VERSION 5.7 ;
BUSBITCHARS "[]" ;
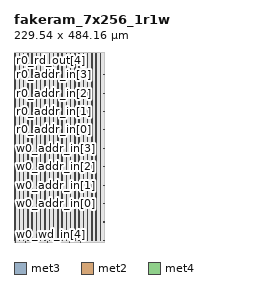
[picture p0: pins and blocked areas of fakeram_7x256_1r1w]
MACRO fakeram_7x256_1r1w
  FOREIGN fakeram_7x256_1r1w 0 0 ;
  SYMMETRY X Y R90 ;
  SIZE 229.540 BY 484.160 ;
  CLASS BLOCK ;
  PIN w0_wd_in[0]
    DIRECTION INPUT ;
    USE SIGNAL ;
    SHAPE ABUTMENT ;
    PORT
      LAYER met3 ;
      RECT 0.000 3.930 0.900 4.230 ;
    END
  END w0_wd_in[0]
  PIN w0_wd_in[1]
    DIRECTION INPUT ;
    USE SIGNAL ;
    SHAPE ABUTMENT ;
    PORT
      LAYER met3 ;
      RECT 0.000 50.850 0.900 51.150 ;
    END
  END w0_wd_in[1]
  PIN w0_wd_in[2]
    DIRECTION INPUT ;
    USE SIGNAL ;
    SHAPE ABUTMENT ;
    PORT
      LAYER met3 ;
      RECT 228.640 3.930 229.540 4.230 ;
    END
  END w0_wd_in[2]
  PIN w0_wd_in[3]
    DIRECTION INPUT ;
    USE SIGNAL ;
    SHAPE ABUTMENT ;
    PORT
      LAYER met3 ;
      RECT 228.640 50.850 229.540 51.150 ;
    END
  END w0_wd_in[3]
  PIN w0_wd_in[4]
    DIRECTION OUTPUT ;
    USE SIGNAL ;
    SHAPE ABUTMENT ;
    PORT
      LAYER met2 ;
      RECT 2.690 0.000 2.830 0.420 ;
    END
  END w0_wd_in[4]
  PIN w0_wd_in[5]
    DIRECTION OUTPUT ;
    USE SIGNAL ;
    SHAPE ABUTMENT ;
    PORT
      LAYER met2 ;
      RECT 30.290 0.000 30.430 0.420 ;
    END
  END w0_wd_in[5]
  PIN w0_wd_in[6]
    DIRECTION OUTPUT ;
    USE SIGNAL ;
    SHAPE ABUTMENT ;
    PORT
      LAYER met2 ;
      RECT 57.890 0.000 58.030 0.420 ;
    END
  END w0_wd_in[6]
  PIN r0_rd_out[0]
    DIRECTION OUTPUT ;
    USE SIGNAL ;
    SHAPE ABUTMENT ;
    PORT
      LAYER met2 ;
      RECT 85.490 0.000 85.630 0.420 ;
    END
  END r0_rd_out[0]
  PIN r0_rd_out[1]
    DIRECTION OUTPUT ;
    USE SIGNAL ;
    SHAPE ABUTMENT ;
    PORT
      LAYER met2 ;
      RECT 113.090 0.000 113.230 0.420 ;
    END
  END r0_rd_out[1]
  PIN r0_rd_out[2]
    DIRECTION OUTPUT ;
    USE SIGNAL ;
    SHAPE ABUTMENT ;
    PORT
      LAYER met2 ;
      RECT 140.690 0.000 140.830 0.420 ;
    END
  END r0_rd_out[2]
  PIN r0_rd_out[3]
    DIRECTION OUTPUT ;
    USE SIGNAL ;
    SHAPE ABUTMENT ;
    PORT
      LAYER met2 ;
      RECT 168.290 0.000 168.430 0.420 ;
    END
  END r0_rd_out[3]
  PIN r0_rd_out[4]
    DIRECTION OUTPUT ;
    USE SIGNAL ;
    SHAPE ABUTMENT ;
    PORT
      LAYER met2 ;
      RECT 2.690 483.740 2.830 484.160 ;
    END
  END r0_rd_out[4]
  PIN r0_rd_out[5]
    DIRECTION OUTPUT ;
    USE SIGNAL ;
    SHAPE ABUTMENT ;
    PORT
      LAYER met2 ;
      RECT 27.070 483.740 27.210 484.160 ;
    END
  END r0_rd_out[5]
  PIN r0_rd_out[6]
    DIRECTION OUTPUT ;
    USE SIGNAL ;
    SHAPE ABUTMENT ;
    PORT
      LAYER met2 ;
      RECT 51.450 483.740 51.590 484.160 ;
    END
  END r0_rd_out[6]
  PIN w0_addr_in[0]
    DIRECTION INPUT ;
    USE SIGNAL ;
    SHAPE ABUTMENT ;
    PORT
      LAYER met3 ;
      RECT 0.000 97.770 0.900 98.070 ;
    END
  END w0_addr_in[0]
  PIN w0_addr_in[1]
    DIRECTION INPUT ;
    USE SIGNAL ;
    SHAPE ABUTMENT ;
    PORT
      LAYER met3 ;
      RECT 0.000 144.690 0.900 144.990 ;
    END
  END w0_addr_in[1]
  PIN w0_addr_in[2]
    DIRECTION INPUT ;
    USE SIGNAL ;
    SHAPE ABUTMENT ;
    PORT
      LAYER met3 ;
      RECT 0.000 191.610 0.900 191.910 ;
    END
  END w0_addr_in[2]
  PIN w0_addr_in[3]
    DIRECTION INPUT ;
    USE SIGNAL ;
    SHAPE ABUTMENT ;
    PORT
      LAYER met3 ;
      RECT 0.000 238.530 0.900 238.830 ;
    END
  END w0_addr_in[3]
  PIN w0_addr_in[4]
    DIRECTION INPUT ;
    USE SIGNAL ;
    SHAPE ABUTMENT ;
    PORT
      LAYER met3 ;
      RECT 228.640 97.770 229.540 98.070 ;
    END
  END w0_addr_in[4]
  PIN w0_addr_in[5]
    DIRECTION INPUT ;
    USE SIGNAL ;
    SHAPE ABUTMENT ;
    PORT
      LAYER met3 ;
      RECT 228.640 144.690 229.540 144.990 ;
    END
  END w0_addr_in[5]
  PIN w0_addr_in[6]
    DIRECTION INPUT ;
    USE SIGNAL ;
    SHAPE ABUTMENT ;
    PORT
      LAYER met3 ;
      RECT 228.640 191.610 229.540 191.910 ;
    END
  END w0_addr_in[6]
  PIN w0_addr_in[7]
    DIRECTION INPUT ;
    USE SIGNAL ;
    SHAPE ABUTMENT ;
    PORT
      LAYER met3 ;
      RECT 228.640 238.530 229.540 238.830 ;
    END
  END w0_addr_in[7]
  PIN r0_addr_in[0]
    DIRECTION INPUT ;
    USE SIGNAL ;
    SHAPE ABUTMENT ;
    PORT
      LAYER met3 ;
      RECT 0.000 285.450 0.900 285.750 ;
    END
  END r0_addr_in[0]
  PIN r0_addr_in[1]
    DIRECTION INPUT ;
    USE SIGNAL ;
    SHAPE ABUTMENT ;
    PORT
      LAYER met3 ;
      RECT 0.000 332.370 0.900 332.670 ;
    END
  END r0_addr_in[1]
  PIN r0_addr_in[2]
    DIRECTION INPUT ;
    USE SIGNAL ;
    SHAPE ABUTMENT ;
    PORT
      LAYER met3 ;
      RECT 0.000 379.290 0.900 379.590 ;
    END
  END r0_addr_in[2]
  PIN r0_addr_in[3]
    DIRECTION INPUT ;
    USE SIGNAL ;
    SHAPE ABUTMENT ;
    PORT
      LAYER met3 ;
      RECT 0.000 426.210 0.900 426.510 ;
    END
  END r0_addr_in[3]
  PIN r0_addr_in[4]
    DIRECTION INPUT ;
    USE SIGNAL ;
    SHAPE ABUTMENT ;
    PORT
      LAYER met3 ;
      RECT 228.640 285.450 229.540 285.750 ;
    END
  END r0_addr_in[4]
  PIN r0_addr_in[5]
    DIRECTION INPUT ;
    USE SIGNAL ;
    SHAPE ABUTMENT ;
    PORT
      LAYER met3 ;
      RECT 228.640 332.370 229.540 332.670 ;
    END
  END r0_addr_in[5]
  PIN r0_addr_in[6]
    DIRECTION INPUT ;
    USE SIGNAL ;
    SHAPE ABUTMENT ;
    PORT
      LAYER met3 ;
      RECT 228.640 379.290 229.540 379.590 ;
    END
  END r0_addr_in[6]
  PIN r0_addr_in[7]
    DIRECTION INPUT ;
    USE SIGNAL ;
    SHAPE ABUTMENT ;
    PORT
      LAYER met3 ;
      RECT 228.640 426.210 229.540 426.510 ;
    END
  END r0_addr_in[7]
  PIN w0_we_in
    DIRECTION INPUT ;
    USE SIGNAL ;
    SHAPE ABUTMENT ;
    PORT
      LAYER met2 ;
      RECT 75.830 483.740 75.970 484.160 ;
    END
  END w0_we_in
  PIN w0_ce_in
    DIRECTION INPUT ;
    USE SIGNAL ;
    SHAPE ABUTMENT ;
    PORT
      LAYER met2 ;
      RECT 100.210 483.740 100.350 484.160 ;
    END
  END w0_ce_in
  PIN w0_clk
    DIRECTION INPUT ;
    USE SIGNAL ;
    SHAPE ABUTMENT ;
    PORT
      LAYER met2 ;
      RECT 124.590 483.740 124.730 484.160 ;
    END
  END w0_clk
  PIN r0_ce_in
    DIRECTION INPUT ;
    USE SIGNAL ;
    SHAPE ABUTMENT ;
    PORT
      LAYER met2 ;
      RECT 148.970 483.740 149.110 484.160 ;
    END
  END r0_ce_in
  PIN r0_clk
    DIRECTION INPUT ;
    USE SIGNAL ;
    SHAPE ABUTMENT ;
    PORT
      LAYER met2 ;
      RECT 173.350 483.740 173.490 484.160 ;
    END
  END r0_clk
  PIN VSS
    DIRECTION INOUT ;
    USE GROUND ;
    PORT
      LAYER met4 ;
      RECT 2.160 4.080 3.360 480.080 ;
      RECT 13.040 4.080 14.240 480.080 ;
      RECT 23.920 4.080 25.120 480.080 ;
      RECT 34.800 4.080 36.000 480.080 ;
      RECT 45.680 4.080 46.880 480.080 ;
      RECT 56.560 4.080 57.760 480.080 ;
      RECT 67.440 4.080 68.640 480.080 ;
      RECT 78.320 4.080 79.520 480.080 ;
      RECT 89.200 4.080 90.400 480.080 ;
      RECT 100.080 4.080 101.280 480.080 ;
      RECT 110.960 4.080 112.160 480.080 ;
      RECT 121.840 4.080 123.040 480.080 ;
      RECT 132.720 4.080 133.920 480.080 ;
      RECT 143.600 4.080 144.800 480.080 ;
      RECT 154.480 4.080 155.680 480.080 ;
      RECT 165.360 4.080 166.560 480.080 ;
      RECT 176.240 4.080 177.440 480.080 ;
      RECT 187.120 4.080 188.320 480.080 ;
      RECT 198.000 4.080 199.200 480.080 ;
      RECT 208.880 4.080 210.080 480.080 ;
      RECT 219.760 4.080 220.960 480.080 ;
    END
  END VSS
  PIN VDD
    DIRECTION INOUT ;
    USE POWER ;
    PORT
      LAYER met4 ;
      RECT 2.160 4.080 3.360 480.080 ;
      RECT 13.040 4.080 14.240 480.080 ;
      RECT 23.920 4.080 25.120 480.080 ;
      RECT 34.800 4.080 36.000 480.080 ;
      RECT 45.680 4.080 46.880 480.080 ;
      RECT 56.560 4.080 57.760 480.080 ;
      RECT 67.440 4.080 68.640 480.080 ;
      RECT 78.320 4.080 79.520 480.080 ;
      RECT 89.200 4.080 90.400 480.080 ;
      RECT 100.080 4.080 101.280 480.080 ;
      RECT 110.960 4.080 112.160 480.080 ;
      RECT 121.840 4.080 123.040 480.080 ;
      RECT 132.720 4.080 133.920 480.080 ;
      RECT 143.600 4.080 144.800 480.080 ;
      RECT 154.480 4.080 155.680 480.080 ;
      RECT 165.360 4.080 166.560 480.080 ;
      RECT 176.240 4.080 177.440 480.080 ;
      RECT 187.120 4.080 188.320 480.080 ;
      RECT 198.000 4.080 199.200 480.080 ;
      RECT 208.880 4.080 210.080 480.080 ;
      RECT 219.760 4.080 220.960 480.080 ;
    END
  END VDD
  OBS
    LAYER met1 ;
    RECT 0 0 229.540 484.160 ;
    LAYER met2 ;
    RECT 0 0 229.540 484.160 ;
    LAYER met3 ;
    RECT 0 0 229.540 484.160 ;
    LAYER met4 ;
    RECT 0 0 229.540 484.160 ;
  END
END fakeram_7x256_1r1w

END LIBRARY
